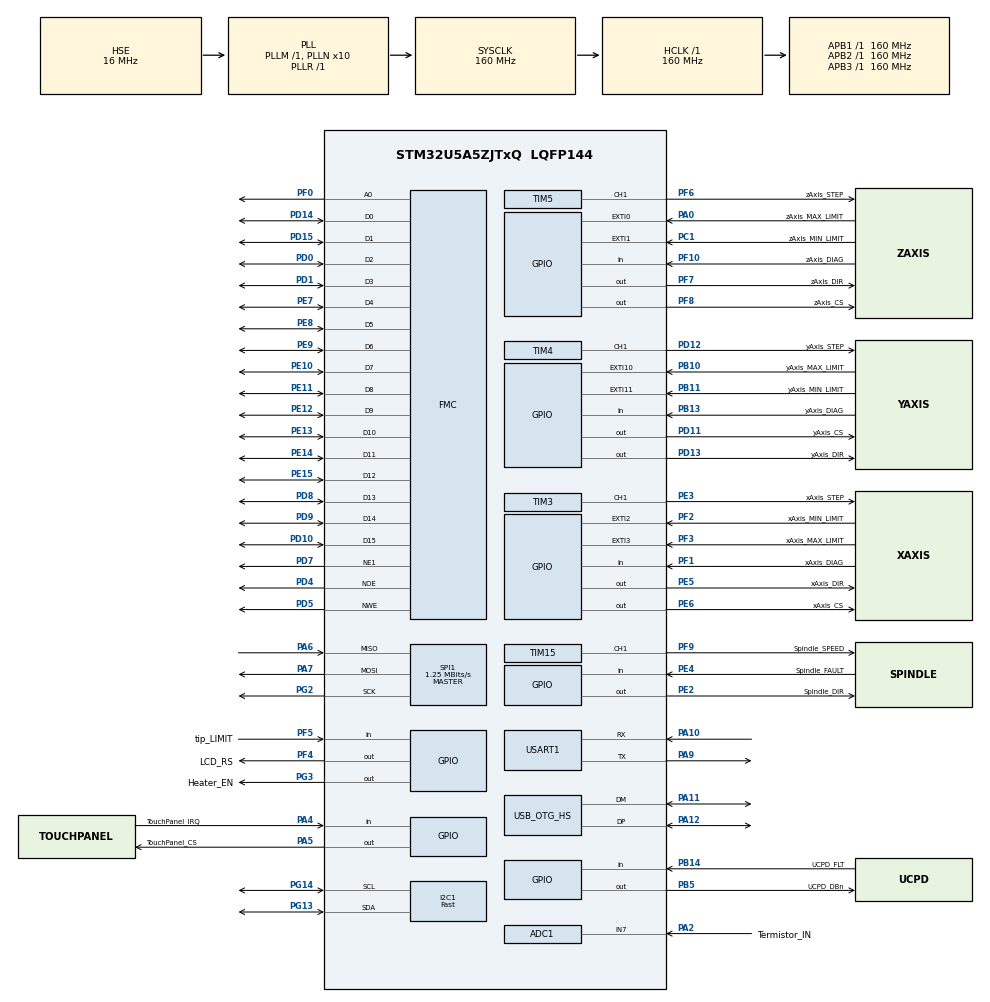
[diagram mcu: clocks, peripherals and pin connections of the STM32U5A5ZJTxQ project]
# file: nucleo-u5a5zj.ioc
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ADC1.Channel-5\#ChannelRegularConversion=ADC_CHANNEL_7
ADC1.MonitoredBy-5\#ChannelRegularConversion=__NULL
ADC1.NbrOfConversionFlag=1
ADC1.OffsetNumber-5\#ChannelRegularConversion=ADC_OFFSET_NONE
ADC1.Rank-5\#ChannelRegularConversion=1
ADC1.SamplingTime-5\#ChannelRegularConversion=ADC_SAMPLETIME_5CYCLE
ADC1.master=1
CORTEX_M33_NS.userName=CORTEX_M33
FMC.AddressSetupTime1=3
FMC.BusTurnAroundDuration1=2
FMC.DataHoldTime1=2
FMC.DataSetupTime1=2
I2C1.I2C_Speed_Mode=I2C_Fast
I2C1.Timing=0x00F07BFF
Mcu.Family=STM32U5
Mcu.Name=STM32U5A5ZJTxQ
Mcu.Package=LQFP144
NUCLEO-U5A5ZJ-Q.BUTTON=2
NUCLEO-U5A5ZJ-Q.LD1=true
NUCLEO-U5A5ZJ-Q.LD2=true
NUCLEO-U5A5ZJ-Q.LD3=false
NVIC.EXTI0_IRQn=true\:0\:0\:false\:false\:true\:true\:true\:true
NVIC.EXTI10_IRQn=true\:0\:0\:false\:false\:true\:true\:true\:true
NVIC.EXTI11_IRQn=true\:0\:0\:false\:false\:true\:true\:true\:true
NVIC.EXTI1_IRQn=true\:0\:0\:false\:false\:true\:true\:true\:true
NVIC.EXTI2_IRQn=true\:0\:0\:false\:false\:true\:true\:true\:true
NVIC.EXTI3_IRQn=true\:0\:0\:false\:false\:true\:true\:true\:true
NVIC.PriorityGroup=NVIC_PRIORITYGROUP_4
NVIC.TIM3_IRQn=true\:0\:0\:false\:false\:true\:true\:true\:true
NVIC.TIM4_IRQn=true\:0\:0\:false\:false\:true\:true\:true\:true
NVIC.TIM5_IRQn=true\:0\:0\:false\:false\:true\:true\:true\:true
PA0.GPIO_Label=zAxis_MAX_LIMIT
PA0.GPIO_ModeDefaultEXTI=GPIO_MODE_IT_RISING_FALLING
PA0.GPIO_PuPd=GPIO_PULLUP
PA0.Signal=GPXTI0
PA10.Mode=Asynchronous
PA10.Signal=USART1_RX
PA11.Mode=Internal_Phy_Device
PA11.Signal=USB_OTG_HS_DM
PA12.Mode=Internal_Phy_Device
PA12.Signal=USB_OTG_HS_DP
PA13\ (JTMS/SWDIO).Mode=Trace_Asynchronous_SW
PA13\ (JTMS/SWDIO).Signal=DEBUG_JTMS-SWDIO
PA14\ (JTCK/SWCLK).Mode=Trace_Asynchronous_SW
PA14\ (JTCK/SWCLK).Signal=DEBUG_JTCK-SWCLK
PA15\ (JTDI).Signal=UCPD1_CC1
PA2.GPIO_Label=Termistor_IN
PA2.Mode=IN7-Single-Ended
PA2.Signal=ADC1_IN7
PA4.GPIO_Label=TouchPanel_IRQ
PA4.Signal=GPIO_Input
PA5.GPIO_Label=TouchPanel_CS
PA5.Signal=GPIO_Output
PA6.Mode=Full_Duplex_Master
PA6.Signal=SPI1_MISO
PA7.Mode=Full_Duplex_Master
PA7.Signal=SPI1_MOSI
PA9.Mode=Asynchronous
PA9.Signal=USART1_TX
PB10.GPIO_Label=yAxis_MAX_LIMIT
PB10.GPIO_ModeDefaultEXTI=GPIO_MODE_IT_FALLING
PB10.GPIO_PuPd=GPIO_PULLUP
PB10.Signal=GPXTI10
PB11.GPIO_Label=yAxis_MIN_LIMIT
PB11.GPIO_ModeDefaultEXTI=GPIO_MODE_IT_FALLING
PB11.GPIO_PuPd=GPIO_PULLUP
PB11.Signal=GPXTI11
PB13.GPIO_Label=yAxis_DIAG
PB13.Signal=GPIO_Input
PB14.GPIO_Label=UCPD_FLT
PB14.Signal=GPIO_Input
PB15.Signal=UCPD1_CC2
PB3\ (JTDO/TRACESWO).Mode=Trace_Asynchronous_SW
PB3\ (JTDO/TRACESWO).Signal=DEBUG_JTDO-SWO
PB5.GPIO_Label=UCPD_DBn
PB5.Signal=GPIO_Output
PC1.GPIO_Label=zAxis_MIN_LIMIT
PC1.GPIO_ModeDefaultEXTI=GPIO_MODE_IT_FALLING
PC1.GPIO_PuPd=GPIO_PULLUP
PC1.Signal=GPXTI1
PC14-OSC32_IN\ (PC14).Mode=LSE-External-Oscillator
PC14-OSC32_IN\ (PC14).Signal=RCC_OSC32_IN
PC15-OSC32_OUT\ (PC15).Mode=LSE-External-Oscillator
PC15-OSC32_OUT\ (PC15).Signal=RCC_OSC32_OUT
PD0.Signal=FMC_D2_DA2
PD1.Signal=FMC_D3_DA3
PD10.Signal=FMC_D15_DA15
PD11.GPIO_Label=yAxis_CS
PD11.Signal=GPIO_Output
PD12.GPIO_Label=yAxis_STEP
PD12.Signal=S_TIM4_CH1
PD13.GPIO_Label=yAxis_DIR
PD13.Signal=GPIO_Output
PD14.Signal=FMC_D0_DA0
PD15.Signal=FMC_D1_DA1
PD4.Signal=FMC_NOE
PD5.Signal=FMC_NWE
PD7.Mode=NorPsramChipSelect1_1
PD7.Signal=FMC_NE1
PD8.Signal=FMC_D13_DA13
PD9.Signal=FMC_D14_DA14
PE10.Signal=FMC_D7_DA7
PE11.Signal=FMC_D8_DA8
PE12.Signal=FMC_D9_DA9
PE13.Signal=FMC_D10_DA10
PE14.Signal=FMC_D11_DA11
PE15.Signal=FMC_D12_DA12
PE2.GPIO_Label=Spindle_DIR
PE2.Signal=GPIO_Output
PE3.GPIO_Label=xAxis_STEP
PE3.Signal=S_TIM3_CH1
PE4.GPIO_Label=Spindle_FAULT
PE4.Signal=GPIO_Input
PE5.GPIO_Label=xAxis_DIR
PE5.Signal=GPIO_Output
PE6.GPIO_Label=xAxis_CS
PE6.Signal=GPIO_Output
PE7.Signal=FMC_D4_DA4
PE8.Signal=FMC_D5_DA5
PE9.Signal=FMC_D6_DA6
PF0.Signal=FMC_A0
PF1.GPIO_Label=xAxis_DIAG
PF1.Signal=GPIO_Input
PF10.GPIO_Label=zAxis_DIAG
PF10.Signal=GPIO_Input
PF2.GPIO_Label=xAxis_MIN_LIMIT
PF2.GPIO_ModeDefaultEXTI=GPIO_MODE_IT_FALLING
PF2.GPIO_PuPd=GPIO_PULLUP
PF2.Signal=GPXTI2
PF3.GPIO_Label=xAxis_MAX_LIMIT
PF3.GPIO_ModeDefaultEXTI=GPIO_MODE_IT_FALLING
PF3.GPIO_PuPd=GPIO_PULLUP
PF3.Signal=GPXTI3
PF4.GPIO_Label=LCD_RS
PF4.Signal=GPIO_Output
PF5.GPIO_Label=tip_LIMIT
PF5.GPIO_PuPd=GPIO_PULLUP
PF5.Signal=GPIO_Input
PF6.GPIO_Label=zAxis_STEP
PF6.Signal=S_TIM5_CH1
PF7.GPIO_Label=zAxis_DIR
PF7.Signal=GPIO_Output
PF8.GPIO_Label=zAxis_CS
PF8.Signal=GPIO_Output
PF9.GPIO_Label=Spindle_SPEED
PF9.Signal=S_TIM15_CH1
PG13.Mode=I2C
PG13.Signal=I2C1_SDA
PG14.Mode=I2C
PG14.Signal=I2C1_SCL
PG2.Mode=Full_Duplex_Master
PG2.Signal=SPI1_SCK
PG3.GPIO_Label=Heater_EN
PG3.Signal=GPIO_Output
PH0-OSC_IN\ (PH0).Mode=HSE-External-Oscillator
PH0-OSC_IN\ (PH0).Signal=RCC_OSC_IN
PH1-OSC_OUT\ (PH1).Mode=HSE-External-Oscillator
PH1-OSC_OUT\ (PH1).Signal=RCC_OSC_OUT
PWR.PowerMode=PWR_SMPS_SUPPLY
ProjectManager.HeapSize=0x200
ProjectManager.StackSize=0x400
ProjectManager.TargetToolchain=STM32CubeIDE
RCC.ADCCLockSelection=RCC_ADCDACCLKSOURCE_HSE
RCC.ADCFreq_Value=16000000
RCC.AHBFreq_Value=160000000
RCC.APB1Freq_Value=160000000
RCC.APB1TimFreq_Value=160000000
RCC.APB2Freq_Value=160000000
RCC.APB2TimFreq_Value=160000000
RCC.APB3Freq_Value=160000000
RCC.CortexFreq_Value=160000000
RCC.DACCLockSelectionVirtual=RCC_DAC1CLKSOURCE_LSI
RCC.EPOD_VALUE=16000000
RCC.HCLKFreq_Value=160000000
RCC.HSE_VALUE=16000000
RCC.HSI48_VALUE=48000000
RCC.HSI_VALUE=16000000
RCC.LSIDIV_VALUE=32000
RCC.MSIClockRange=RCC_MSIRANGE_0
RCC.MSI_VALUE=48000000
RCC.PLL1P=8
RCC.PLL1R=1
RCC.PLL2FRACN=0
RCC.PLL3FRACN=0
RCC.PLLFRACN=0
RCC.PLLN=10
RCC.PLLSourceVirtual=RCC_PLLSOURCE_HSE
RCC.SYSCLKFreq_VALUE=160000000
RCC.SYSCLKSource=RCC_SYSCLKSOURCE_PLLCLK
RCC.USBPHYCLockSelection=RCC_USBPHYCLKSOURCE_HSE
RCC.VCOOutputFreq_Value=160000000
SH.FMC_A0.0=FMC_A0,A0_1
SH.FMC_D0_DA0.0=FMC_D0,16b-d1
SH.FMC_D10_DA10.0=FMC_D10,16b-d1
SH.FMC_D11_DA11.0=FMC_D11,16b-d1
SH.FMC_D12_DA12.0=FMC_D12,16b-d1
SH.FMC_D13_DA13.0=FMC_D13,16b-d1
SH.FMC_D14_DA14.0=FMC_D14,16b-d1
SH.FMC_D15_DA15.0=FMC_D15,16b-d1
SH.FMC_D1_DA1.0=FMC_D1,16b-d1
SH.FMC_D2_DA2.0=FMC_D2,16b-d1
SH.FMC_D3_DA3.0=FMC_D3,16b-d1
SH.FMC_D4_DA4.0=FMC_D4,16b-d1
SH.FMC_D5_DA5.0=FMC_D5,16b-d1
SH.FMC_D6_DA6.0=FMC_D6,16b-d1
SH.FMC_D7_DA7.0=FMC_D7,16b-d1
SH.FMC_D8_DA8.0=FMC_D8,16b-d1
SH.FMC_D9_DA9.0=FMC_D9,16b-d1
SH.FMC_NOE.0=FMC_NOE,Lcd1
SH.FMC_NWE.0=FMC_NWE,Lcd1
SH.S_TIM15_CH1.0=TIM15_CH1,PWM Generation1 CH1
SH.S_TIM3_CH1.0=TIM3_CH1,Output Compare1 CH1
SH.S_TIM4_CH1.0=TIM4_CH1,Output Compare1 CH1
SH.S_TIM5_CH1.0=TIM5_CH1,Output Compare1 CH1
SPI1.BaudRatePrescaler=SPI_BAUDRATEPRESCALER_128
SPI1.CalculateBaudRate=1.25 MBits/s
SPI1.DataSize=SPI_DATASIZE_8BIT
SPI1.Direction=SPI_DIRECTION_2LINES
SPI1.Mode=SPI_MODE_MASTER
SPI1.VirtualType=VM_MASTER
STMicroelectronics.X-CUBE-TOUCHGFX.4.26.0.ApplicationCcGraphicsJjApplication=TouchGFXOoGenerator
STMicroelectronics.X-CUBE-TOUCHGFX.4.26.0.tgfx_buffering_strategy=Double
STMicroelectronics.X-CUBE-TOUCHGFX.4.26.0.tgfx_custom_height=800
STMicroelectronics.X-CUBE-TOUCHGFX.4.26.0.tgfx_custom_width=480
STMicroelectronics.X-CUBE-TOUCHGFX.4.26.0.tgfx_display_interface=disp_fmc
STMicroelectronics.X-CUBE-TOUCHGFX.4.26.0.tgfx_hardware_accelerator=dma_2d
STMicroelectronics.X-CUBE-TOUCHGFX.4.26.0.tgfx_location=Allocate
STMicroelectronics.X-CUBE-TOUCHGFX.4.26.0_IsPackSelfContextualization=true
TIM15.Channel-PWM\ Generation1\ CH1=TIM_CHANNEL_1
TIM15.Prescaler=159
TIM3.Channel-Output\ Compare1\ CH1=TIM_CHANNEL_1
TIM3.OCMode_1=TIM_OCMODE_TOGGLE
TIM3.Prescaler=159
TIM3.PulseNoDither_1=4294967295
TIM4.Channel-Output\ Compare1\ CH1=TIM_CHANNEL_1
TIM4.OCMode_1=TIM_OCMODE_TOGGLE
TIM4.Prescaler=159
TIM4.PulseNoDither_1=4294967295
TIM5.Channel-Output\ Compare1\ CH1=TIM_CHANNEL_1
TIM5.OCMode_1=TIM_OCMODE_TOGGLE
TIM5.Prescaler=159
TIM5.PulseNoDither_1=4294967295
USART1.VirtualMode-Asynchronous=VM_ASYNC
USB_OTG_HS.VirtualMode=Device_HS
VP_CRC_VS_CRC.Mode=CRC_Activate
VP_DMA2D_VS_DMA2D.Mode=DMA2D_Activate
VP_ICACHE_VS_ICACHE.Mode=DirectMappedCache
VP_LPBAMQUEUE_VS_QUEUE.Mode=QUEUEMODE
VP_LPBAM_VS_SIG1.Mode=SmartRun
VP_LPBAM_VS_SIG4.Mode=LPDMA1
VP_MEMORYMAP_VS_MEMORYMAP.Mode=CurAppReg
VP_NUCLEO-U5A5ZJ-Q_VS_BSP_COMMON.Mode=COMMON
VP_PWR_VS_DBSignals.Mode=DisableDeadBatterySignals
VP_PWR_VS_LPOM.Mode=PowerOptimisation
VP_PWR_VS_SECSignals.Mode=Security/Privilege
VP_PWR_Vdda.Mode=isolationVdda
VP_STMicroelectronics.X-CUBE-TOUCHGFX_VS_GraphicsJjApplication_4.26.0.Mode=GraphicsJjApplication
VP_TIM15_VS_ClockSourceINT.Mode=Internal
VP_TIM3_VS_ClockSourceINT.Mode=Internal
VP_TIM4_VS_ClockSourceINT.Mode=Internal
VP_TIM5_VS_ClockSourceINT.Mode=Internal
board=NUCLEO-U5A5ZJ-Q

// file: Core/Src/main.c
/* USER CODE BEGIN Header */
/**
 ******************************************************************************
 * @file           : main.c
 * @brief          : Main program body
 ******************************************************************************
 * @attention
 *3
 * Copyright (c) 2025 STMicroelectronics.
 * All rights reserved.
 *
 * This software is licensed under terms that can be found in the LICENSE
 * file in the root directory of this software component. If no LICENSE
 * file comes with this software, it is provided AS-IS.
 *
 ******************************************************************************
 */
/* USER CODE END Header */
#include "main.h"
#include "app_touchgfx.h"

ADC_HandleTypeDef hadc1;

CRC_HandleTypeDef hcrc;

DMA2D_HandleTypeDef hdma2d;

I2C_HandleTypeDef hi2c1;

SPI_HandleTypeDef hspi1;

TIM_HandleTypeDef htim3;
TIM_HandleTypeDef htim4;
TIM_HandleTypeDef htim5;
TIM_HandleTypeDef htim15;

UART_HandleTypeDef huart1;

PCD_HandleTypeDef hpcd_USB_OTG_HS;

SRAM_HandleTypeDef hsram1;

void SystemClock_Config(void);
static void SystemPower_Config(void);
static void MX_GPIO_Init(void);
static void MX_ICACHE_Init(void);
static void MX_USB_OTG_HS_PCD_Init(void);
static void MX_ADC1_Init(void);
static void MX_CRC_Init(void);
static void MX_DMA2D_Init(void);
static void MX_FMC_Init(void);
static void MX_SPI1_Init(void);
static void MX_USART1_UART_Init(void);
static void MX_TIM3_Init(void);
static void MX_TIM4_Init(void);
static void MX_TIM5_Init(void);
static void MX_TIM15_Init(void);
static void MX_I2C1_Init(void);

int main(void)
{

  /* MCU Configuration--------------------------------------------------------*/

  /* Reset of all peripherals, Initializes the Flash interface and the Systick. */
  HAL_Init();

  /* Configure the System Power */
  SystemPower_Config();

  /* Configure the system clock */
  SystemClock_Config();

  /* Initialize all configured peripherals */
  MX_GPIO_Init();
  MX_ICACHE_Init();
  MX_USB_OTG_HS_PCD_Init();
  MX_ADC1_Init();
  MX_CRC_Init();
  MX_DMA2D_Init();
  MX_FMC_Init();
  MX_SPI1_Init();
  MX_USART1_UART_Init();
  MX_TIM3_Init();
  MX_TIM4_Init();
  MX_TIM5_Init();
  MX_TIM15_Init();
  MX_I2C1_Init();
  MX_TouchGFX_Init();

  /* Initialize leds */
  BSP_LED_Init(LED_GREEN);
  BSP_LED_Init(LED_BLUE);

  /* Initialize User push-button without interrupt mode. */
  BSP_PB_Init(BUTTON_USER, BUTTON_MODE_GPIO);

  /* Infinite loop */
  /* USER CODE BEGIN WHILE */
    ATC_Init();

    while (1) {
        ATC_Loop();

    /* USER CODE END WHILE */

  MX_TouchGFX_Process();
    }
}

void SystemClock_Config(void)
{
  RCC_OscInitTypeDef RCC_OscInitStruct = {0};
  RCC_ClkInitTypeDef RCC_ClkInitStruct = {0};

  /** Configure the main internal regulator output voltage
  */
  if (HAL_PWREx_ControlVoltageScaling(PWR_REGULATOR_VOLTAGE_SCALE1) != HAL_OK)
  {
    Error_Handler();
  }

  /** Initializes the CPU, AHB and APB buses clocks
  */
  RCC_OscInitStruct.OscillatorType = RCC_OSCILLATORTYPE_HSE;
  RCC_OscInitStruct.HSEState = RCC_HSE_ON;
  RCC_OscInitStruct.PLL.PLLState = RCC_PLL_ON;
  RCC_OscInitStruct.PLL.PLLSource = RCC_PLLSOURCE_HSE;
  RCC_OscInitStruct.PLL.PLLMBOOST = RCC_PLLMBOOST_DIV1;
  RCC_OscInitStruct.PLL.PLLM = 1;
  RCC_OscInitStruct.PLL.PLLN = 10;
  RCC_OscInitStruct.PLL.PLLP = 8;
  RCC_OscInitStruct.PLL.PLLQ = 2;
  RCC_OscInitStruct.PLL.PLLR = 1;
  RCC_OscInitStruct.PLL.PLLRGE = RCC_PLLVCIRANGE_1;
  RCC_OscInitStruct.PLL.PLLFRACN = 0;
  if (HAL_RCC_OscConfig(&RCC_OscInitStruct) != HAL_OK)
  {
    Error_Handler();
  }

  /** Initializes the CPU, AHB and APB buses clocks
  */
  RCC_ClkInitStruct.ClockType = RCC_CLOCKTYPE_HCLK|RCC_CLOCKTYPE_SYSCLK
                              |RCC_CLOCKTYPE_PCLK1|RCC_CLOCKTYPE_PCLK2
                              |RCC_CLOCKTYPE_PCLK3;
  RCC_ClkInitStruct.SYSCLKSource = RCC_SYSCLKSOURCE_PLLCLK;
  RCC_ClkInitStruct.AHBCLKDivider = RCC_SYSCLK_DIV1;
  RCC_ClkInitStruct.APB1CLKDivider = RCC_HCLK_DIV1;
  RCC_ClkInitStruct.APB2CLKDivider = RCC_HCLK_DIV1;
  RCC_ClkInitStruct.APB3CLKDivider = RCC_HCLK_DIV1;

  if (HAL_RCC_ClockConfig(&RCC_ClkInitStruct, FLASH_LATENCY_4) != HAL_OK)
  {
    Error_Handler();
  }
}

/**
  * @brief Power Configuration
  * @retval None
  */
static void SystemPower_Config(void)
{
  HAL_PWREx_EnableVddIO2();

  /*
   * Disable the internal Pull-Up in Dead Battery pins of UCPD peripheral
   */
  HAL_PWREx_DisableUCPDDeadBattery();

  /*
   * Switch to SMPS regulator instead of LDO
   */
  if (HAL_PWREx_ConfigSupply(PWR_SMPS_SUPPLY) != HAL_OK)
  {
    Error_Handler();
  }
}

static void MX_ADC1_Init(void)
{

  ADC_ChannelConfTypeDef sConfig = {0};

  /** Common config
  */
  hadc1.Instance = ADC1;
  hadc1.Init.ClockPrescaler = ADC_CLOCK_ASYNC_DIV1;
  hadc1.Init.Resolution = ADC_RESOLUTION_14B;
  hadc1.Init.GainCompensation = 0;
  hadc1.Init.DataAlign = ADC_DATAALIGN_RIGHT;
  hadc1.Init.ScanConvMode = ADC_SCAN_DISABLE;
  hadc1.Init.EOCSelection = ADC_EOC_SINGLE_CONV;
  hadc1.Init.LowPowerAutoWait = DISABLE;
  hadc1.Init.ContinuousConvMode = DISABLE;
  hadc1.Init.NbrOfConversion = 1;
  hadc1.Init.DiscontinuousConvMode = DISABLE;
  hadc1.Init.ExternalTrigConv = ADC_SOFTWARE_START;
  hadc1.Init.ExternalTrigConvEdge = ADC_EXTERNALTRIGCONVEDGE_NONE;
  hadc1.Init.DMAContinuousRequests = DISABLE;
  hadc1.Init.TriggerFrequencyMode = ADC_TRIGGER_FREQ_HIGH;
  hadc1.Init.Overrun = ADC_OVR_DATA_PRESERVED;
  hadc1.Init.LeftBitShift = ADC_LEFTBITSHIFT_NONE;
  hadc1.Init.ConversionDataManagement = ADC_CONVERSIONDATA_DR;
  hadc1.Init.OversamplingMode = DISABLE;
  if (HAL_ADC_Init(&hadc1) != HAL_OK)
  {
    Error_Handler();
  }

  /** Configure Regular Channel
  */
  sConfig.Channel = ADC_CHANNEL_7;
  sConfig.Rank = ADC_REGULAR_RANK_1;
  sConfig.SamplingTime = ADC_SAMPLETIME_5CYCLE;
  sConfig.SingleDiff = ADC_SINGLE_ENDED;
  sConfig.OffsetNumber = ADC_OFFSET_NONE;
  sConfig.Offset = 0;
  if (HAL_ADC_ConfigChannel(&hadc1, &sConfig) != HAL_OK)
  {
    Error_Handler();
  }

}

static void MX_CRC_Init(void)
{

  hcrc.Instance = CRC;
  hcrc.Init.DefaultPolynomialUse = DEFAULT_POLYNOMIAL_ENABLE;
  hcrc.Init.DefaultInitValueUse = DEFAULT_INIT_VALUE_ENABLE;
  hcrc.Init.InputDataInversionMode = CRC_INPUTDATA_INVERSION_NONE;
  hcrc.Init.OutputDataInversionMode = CRC_OUTPUTDATA_INVERSION_DISABLE;
  hcrc.InputDataFormat = CRC_INPUTDATA_FORMAT_BYTES;
  if (HAL_CRC_Init(&hcrc) != HAL_OK)
  {
    Error_Handler();
  }

}

static void MX_DMA2D_Init(void)
{

  hdma2d.Instance = DMA2D;
  hdma2d.Init.Mode = DMA2D_M2M;
  hdma2d.Init.ColorMode = DMA2D_OUTPUT_ARGB8888;
  hdma2d.Init.OutputOffset = 0;
  hdma2d.Init.BytesSwap = DMA2D_BYTES_REGULAR;
  hdma2d.Init.LineOffsetMode = DMA2D_LOM_PIXELS;
  hdma2d.LayerCfg[1].InputOffset = 0;
  hdma2d.LayerCfg[1].InputColorMode = DMA2D_INPUT_ARGB8888;
  hdma2d.LayerCfg[1].AlphaMode = DMA2D_NO_MODIF_ALPHA;
  hdma2d.LayerCfg[1].InputAlpha = 0;
  hdma2d.LayerCfg[1].AlphaInverted = DMA2D_REGULAR_ALPHA;
  hdma2d.LayerCfg[1].RedBlueSwap = DMA2D_RB_REGULAR;
  if (HAL_DMA2D_Init(&hdma2d) != HAL_OK)
  {
    Error_Handler();
  }
  if (HAL_DMA2D_ConfigLayer(&hdma2d, 1) != HAL_OK)
  {
    Error_Handler();
  }

}

static void MX_I2C1_Init(void)
{

  hi2c1.Instance = I2C1;
  hi2c1.Init.Timing = 0x00F07BFF;
  hi2c1.Init.OwnAddress1 = 0;
  hi2c1.Init.AddressingMode = I2C_ADDRESSINGMODE_7BIT;
  hi2c1.Init.DualAddressMode = I2C_DUALADDRESS_DISABLE;
  hi2c1.Init.OwnAddress2 = 0;
  hi2c1.Init.OwnAddress2Masks = I2C_OA2_NOMASK;
  hi2c1.Init.GeneralCallMode = I2C_GENERALCALL_DISABLE;
  hi2c1.Init.NoStretchMode = I2C_NOSTRETCH_DISABLE;
  if (HAL_I2C_Init(&hi2c1) != HAL_OK)
  {
    Error_Handler();
  }

  /** Configure Analogue filter
  */
  if (HAL_I2CEx_ConfigAnalogFilter(&hi2c1, I2C_ANALOGFILTER_ENABLE) != HAL_OK)
  {
    Error_Handler();
  }

  /** Configure Digital filter
  */
  if (HAL_I2CEx_ConfigDigitalFilter(&hi2c1, 0) != HAL_OK)
  {
    Error_Handler();
  }

}

static void MX_ICACHE_Init(void)
{

  /** Enable instruction cache in 1-way (direct mapped cache)
  */
  if (HAL_ICACHE_ConfigAssociativityMode(ICACHE_1WAY) != HAL_OK)
  {
    Error_Handler();
  }
  if (HAL_ICACHE_Enable() != HAL_OK)
  {
    Error_Handler();
  }

}

static void MX_SPI1_Init(void)
{

  SPI_AutonomousModeConfTypeDef HAL_SPI_AutonomousMode_Cfg_Struct = {0};

  /* SPI1 parameter configuration*/
  hspi1.Instance = SPI1;
  hspi1.Init.Mode = SPI_MODE_MASTER;
  hspi1.Init.Direction = SPI_DIRECTION_2LINES;
  hspi1.Init.DataSize = SPI_DATASIZE_8BIT;
  hspi1.Init.CLKPolarity = SPI_POLARITY_LOW;
  hspi1.Init.CLKPhase = SPI_PHASE_1EDGE;
  hspi1.Init.NSS = SPI_NSS_SOFT;
  hspi1.Init.BaudRatePrescaler = SPI_BAUDRATEPRESCALER_128;
  hspi1.Init.FirstBit = SPI_FIRSTBIT_MSB;
  hspi1.Init.TIMode = SPI_TIMODE_DISABLE;
  hspi1.Init.CRCCalculation = SPI_CRCCALCULATION_DISABLE;
  hspi1.Init.CRCPolynomial = 0x7;
  hspi1.Init.NSSPMode = SPI_NSS_PULSE_ENABLE;
  hspi1.Init.NSSPolarity = SPI_NSS_POLARITY_LOW;
  hspi1.Init.FifoThreshold = SPI_FIFO_THRESHOLD_01DATA;
  hspi1.Init.MasterSSIdleness = SPI_MASTER_SS_IDLENESS_00CYCLE;
  hspi1.Init.MasterInterDataIdleness = SPI_MASTER_INTERDATA_IDLENESS_00CYCLE;
  hspi1.Init.MasterReceiverAutoSusp = SPI_MASTER_RX_AUTOSUSP_DISABLE;
  hspi1.Init.MasterKeepIOState = SPI_MASTER_KEEP_IO_STATE_DISABLE;
  hspi1.Init.IOSwap = SPI_IO_SWAP_DISABLE;
  hspi1.Init.ReadyMasterManagement = SPI_RDY_MASTER_MANAGEMENT_INTERNALLY;
  hspi1.Init.ReadyPolarity = SPI_RDY_POLARITY_HIGH;
  if (HAL_SPI_Init(&hspi1) != HAL_OK)
  {
    Error_Handler();
  }
  HAL_SPI_AutonomousMode_Cfg_Struct.TriggerState = SPI_AUTO_MODE_DISABLE;
  HAL_SPI_AutonomousMode_Cfg_Struct.TriggerSelection = SPI_GRP1_GPDMA_CH0_TCF_TRG;
  HAL_SPI_AutonomousMode_Cfg_Struct.TriggerPolarity = SPI_TRIG_POLARITY_RISING;
  if (HAL_SPIEx_SetConfigAutonomousMode(&hspi1, &HAL_SPI_AutonomousMode_Cfg_Struct) != HAL_OK)
  {
    Error_Handler();
  }

}

static void MX_TIM3_Init(void)
{

  TIM_ClockConfigTypeDef sClockSourceConfig = {0};
  TIM_MasterConfigTypeDef sMasterConfig = {0};
  TIM_OC_InitTypeDef sConfigOC = {0};

  htim3.Instance = TIM3;
  htim3.Init.Prescaler = 159;
  htim3.Init.CounterMode = TIM_COUNTERMODE_UP;
  htim3.Init.Period = 4294967295;
  htim3.Init.ClockDivision = TIM_CLOCKDIVISION_DIV1;
  htim3.Init.AutoReloadPreload = TIM_AUTORELOAD_PRELOAD_DISABLE;
  if (HAL_TIM_Base_Init(&htim3) != HAL_OK)
  {
    Error_Handler();
  }
  sClockSourceConfig.ClockSource = TIM_CLOCKSOURCE_INTERNAL;
  if (HAL_TIM_ConfigClockSource(&htim3, &sClockSourceConfig) != HAL_OK)
  {
    Error_Handler();
  }
  if (HAL_TIM_OC_Init(&htim3) != HAL_OK)
  {
    Error_Handler();
  }
  sMasterConfig.MasterOutputTrigger = TIM_TRGO_RESET;
  sMasterConfig.MasterSlaveMode = TIM_MASTERSLAVEMODE_DISABLE;
  if (HAL_TIMEx_MasterConfigSynchronization(&htim3, &sMasterConfig) != HAL_OK)
  {
    Error_Handler();
  }
  sConfigOC.OCMode = TIM_OCMODE_TOGGLE;
  sConfigOC.Pulse = 4294967295;
  sConfigOC.OCPolarity = TIM_OCPOLARITY_HIGH;
  sConfigOC.OCFastMode = TIM_OCFAST_DISABLE;
  if (HAL_TIM_OC_ConfigChannel(&htim3, &sConfigOC, TIM_CHANNEL_1) != HAL_OK)
  {
    Error_Handler();
  }
  HAL_TIM_MspPostInit(&htim3);

}

static void MX_TIM4_Init(void)
{

  TIM_ClockConfigTypeDef sClockSourceConfig = {0};
  TIM_MasterConfigTypeDef sMasterConfig = {0};
  TIM_OC_InitTypeDef sConfigOC = {0};

  htim4.Instance = TIM4;
  htim4.Init.Prescaler = 159;
  htim4.Init.CounterMode = TIM_COUNTERMODE_UP;
  htim4.Init.Period = 4294967295;
  htim4.Init.ClockDivision = TIM_CLOCKDIVISION_DIV1;
  htim4.Init.AutoReloadPreload = TIM_AUTORELOAD_PRELOAD_DISABLE;
  if (HAL_TIM_Base_Init(&htim4) != HAL_OK)
  {
    Error_Handler();
  }
  sClockSourceConfig.ClockSource = TIM_CLOCKSOURCE_INTERNAL;
  if (HAL_TIM_ConfigClockSource(&htim4, &sClockSourceConfig) != HAL_OK)
  {
    Error_Handler();
  }
  if (HAL_TIM_OC_Init(&htim4) != HAL_OK)
  {
    Error_Handler();
  }
  sMasterConfig.MasterOutputTrigger = TIM_TRGO_RESET;
  sMasterConfig.MasterSlaveMode = TIM_MASTERSLAVEMODE_DISABLE;
  if (HAL_TIMEx_MasterConfigSynchronization(&htim4, &sMasterConfig) != HAL_OK)
  {
    Error_Handler();
  }
  sConfigOC.OCMode = TIM_OCMODE_TOGGLE;
  sConfigOC.Pulse = 4294967295;
  sConfigOC.OCPolarity = TIM_OCPOLARITY_HIGH;
  sConfigOC.OCFastMode = TIM_OCFAST_DISABLE;
  if (HAL_TIM_OC_ConfigChannel(&htim4, &sConfigOC, TIM_CHANNEL_1) != HAL_OK)
  {
    Error_Handler();
  }
  HAL_TIM_MspPostInit(&htim4);

}

static void MX_TIM5_Init(void)
{

  TIM_ClockConfigTypeDef sClockSourceConfig = {0};
  TIM_MasterConfigTypeDef sMasterConfig = {0};
  TIM_OC_InitTypeDef sConfigOC = {0};

  htim5.Instance = TIM5;
  htim5.Init.Prescaler = 159;
  htim5.Init.CounterMode = TIM_COUNTERMODE_UP;
  htim5.Init.Period = 4294967295;
  htim5.Init.ClockDivision = TIM_CLOCKDIVISION_DIV1;
  htim5.Init.AutoReloadPreload = TIM_AUTORELOAD_PRELOAD_DISABLE;
  if (HAL_TIM_Base_Init(&htim5) != HAL_OK)
  {
    Error_Handler();
  }
  sClockSourceConfig.ClockSource = TIM_CLOCKSOURCE_INTERNAL;
  if (HAL_TIM_ConfigClockSource(&htim5, &sClockSourceConfig) != HAL_OK)
  {
    Error_Handler();
  }
  if (HAL_TIM_OC_Init(&htim5) != HAL_OK)
  {
    Error_Handler();
  }
  sMasterConfig.MasterOutputTrigger = TIM_TRGO_RESET;
  sMasterConfig.MasterSlaveMode = TIM_MASTERSLAVEMODE_DISABLE;
  if (HAL_TIMEx_MasterConfigSynchronization(&htim5, &sMasterConfig) != HAL_OK)
  {
    Error_Handler();
  }
  sConfigOC.OCMode = TIM_OCMODE_TOGGLE;
  sConfigOC.Pulse = 4294967295;
  sConfigOC.OCPolarity = TIM_OCPOLARITY_HIGH;
  sConfigOC.OCFastMode = TIM_OCFAST_DISABLE;
  if (HAL_TIM_OC_ConfigChannel(&htim5, &sConfigOC, TIM_CHANNEL_1) != HAL_OK)
  {
    Error_Handler();
  }
  HAL_TIM_MspPostInit(&htim5);

}

static void MX_TIM15_Init(void)
{

  TIM_ClockConfigTypeDef sClockSourceConfig = {0};
  TIM_MasterConfigTypeDef sMasterConfig = {0};
  TIM_OC_InitTypeDef sConfigOC = {0};
  TIM_BreakDeadTimeConfigTypeDef sBreakDeadTimeConfig = {0};

  htim15.Instance = TIM15;
  htim15.Init.Prescaler = 159;
  htim15.Init.CounterMode = TIM_COUNTERMODE_UP;
  htim15.Init.Period = 65535;
  htim15.Init.ClockDivision = TIM_CLOCKDIVISION_DIV1;
  htim15.Init.RepetitionCounter = 0;
  htim15.Init.AutoReloadPreload = TIM_AUTORELOAD_PRELOAD_DISABLE;
  if (HAL_TIM_Base_Init(&htim15) != HAL_OK)
  {
    Error_Handler();
  }
  sClockSourceConfig.ClockSource = TIM_CLOCKSOURCE_INTERNAL;
  if (HAL_TIM_ConfigClockSource(&htim15, &sClockSourceConfig) != HAL_OK)
  {
    Error_Handler();
  }
  if (HAL_TIM_PWM_Init(&htim15) != HAL_OK)
  {
    Error_Handler();
  }
  sMasterConfig.MasterOutputTrigger = TIM_TRGO_RESET;
  sMasterConfig.MasterSlaveMode = TIM_MASTERSLAVEMODE_DISABLE;
  if (HAL_TIMEx_MasterConfigSynchronization(&htim15, &sMasterConfig) != HAL_OK)
  {
    Error_Handler();
  }
  sConfigOC.OCMode = TIM_OCMODE_PWM1;
  sConfigOC.Pulse = 0;
  sConfigOC.OCPolarity = TIM_OCPOLARITY_HIGH;
  sConfigOC.OCNPolarity = TIM_OCNPOLARITY_HIGH;
  sConfigOC.OCFastMode = TIM_OCFAST_DISABLE;
  sConfigOC.OCIdleState = TIM_OCIDLESTATE_RESET;
  sConfigOC.OCNIdleState = TIM_OCNIDLESTATE_RESET;
  if (HAL_TIM_PWM_ConfigChannel(&htim15, &sConfigOC, TIM_CHANNEL_1) != HAL_OK)
  {
    Error_Handler();
  }
  sBreakDeadTimeConfig.OffStateRunMode = TIM_OSSR_DISABLE;
  sBreakDeadTimeConfig.OffStateIDLEMode = TIM_OSSI_DISABLE;
  sBreakDeadTimeConfig.LockLevel = TIM_LOCKLEVEL_OFF;
  sBreakDeadTimeConfig.DeadTime = 0;
  sBreakDeadTimeConfig.BreakState = TIM_BREAK_DISABLE;
  sBreakDeadTimeConfig.BreakPolarity = TIM_BREAKPOLARITY_HIGH;
  sBreakDeadTimeConfig.BreakFilter = 0;
  sBreakDeadTimeConfig.AutomaticOutput = TIM_AUTOMATICOUTPUT_DISABLE;
  if (HAL_TIMEx_ConfigBreakDeadTime(&htim15, &sBreakDeadTimeConfig) != HAL_OK)
  {
    Error_Handler();
  }
  HAL_TIM_MspPostInit(&htim15);

}

static void MX_USART1_UART_Init(void)
{

  huart1.Instance = USART1;
  huart1.Init.BaudRate = 115200;
  huart1.Init.WordLength = UART_WORDLENGTH_8B;
  huart1.Init.StopBits = UART_STOPBITS_1;
  huart1.Init.Parity = UART_PARITY_NONE;
  huart1.Init.Mode = UART_MODE_TX_RX;
  huart1.Init.HwFlowCtl = UART_HWCONTROL_NONE;
  huart1.Init.OverSampling = UART_OVERSAMPLING_16;
  huart1.Init.OneBitSampling = UART_ONE_BIT_SAMPLE_DISABLE;
  huart1.Init.ClockPrescaler = UART_PRESCALER_DIV1;
  huart1.AdvancedInit.AdvFeatureInit = UART_ADVFEATURE_NO_INIT;
  if (HAL_UART_Init(&huart1) != HAL_OK)
  {
    Error_Handler();
  }
  if (HAL_UARTEx_SetTxFifoThreshold(&huart1, UART_TXFIFO_THRESHOLD_1_8) != HAL_OK)
  {
    Error_Handler();
  }
  if (HAL_UARTEx_SetRxFifoThreshold(&huart1, UART_RXFIFO_THRESHOLD_1_8) != HAL_OK)
  {
    Error_Handler();
  }
  if (HAL_UARTEx_DisableFifoMode(&huart1) != HAL_OK)
  {
    Error_Handler();
  }

}

static void MX_USB_OTG_HS_PCD_Init(void)
{

  hpcd_USB_OTG_HS.Instance = USB_OTG_HS;
  hpcd_USB_OTG_HS.Init.dev_endpoints = 9;
  hpcd_USB_OTG_HS.Init.speed = PCD_SPEED_HIGH;
  hpcd_USB_OTG_HS.Init.phy_itface = USB_OTG_HS_EMBEDDED_PHY;
  hpcd_USB_OTG_HS.Init.Sof_enable = DISABLE;
  hpcd_USB_OTG_HS.Init.low_power_enable = DISABLE;
  hpcd_USB_OTG_HS.Init.lpm_enable = DISABLE;
  hpcd_USB_OTG_HS.Init.use_dedicated_ep1 = DISABLE;
  hpcd_USB_OTG_HS.Init.vbus_sensing_enable = DISABLE;
  hpcd_USB_OTG_HS.Init.dma_enable = DISABLE;
  if (HAL_PCD_Init(&hpcd_USB_OTG_HS) != HAL_OK)
  {
    Error_Handler();
  }

}

/* FMC initialization function */
static void MX_FMC_Init(void)
{

  FMC_NORSRAM_TimingTypeDef Timing = {0};

  /** Perform the SRAM1 memory initialization sequence
  */
  hsram1.Instance = FMC_NORSRAM_DEVICE;
  hsram1.Extended = FMC_NORSRAM_EXTENDED_DEVICE;
  /* hsram1.Init */
  hsram1.Init.NSBank = FMC_NORSRAM_BANK1;
  hsram1.Init.DataAddressMux = FMC_DATA_ADDRESS_MUX_DISABLE;
  hsram1.Init.MemoryType = FMC_MEMORY_TYPE_SRAM;
  hsram1.Init.MemoryDataWidth = FMC_NORSRAM_MEM_BUS_WIDTH_16;
  hsram1.Init.BurstAccessMode = FMC_BURST_ACCESS_MODE_DISABLE;
  hsram1.Init.WaitSignalPolarity = FMC_WAIT_SIGNAL_POLARITY_LOW;
  hsram1.Init.WaitSignalActive = FMC_WAIT_TIMING_BEFORE_WS;
  hsram1.Init.WriteOperation = FMC_WRITE_OPERATION_ENABLE;
  hsram1.Init.WaitSignal = FMC_WAIT_SIGNAL_DISABLE;
  hsram1.Init.ExtendedMode = FMC_EXTENDED_MODE_DISABLE;
  hsram1.Init.AsynchronousWait = FMC_ASYNCHRONOUS_WAIT_DISABLE;
  hsram1.Init.WriteBurst = FMC_WRITE_BURST_DISABLE;
  hsram1.Init.ContinuousClock = FMC_CONTINUOUS_CLOCK_SYNC_ONLY;
  hsram1.Init.WriteFifo = FMC_WRITE_FIFO_ENABLE;
  hsram1.Init.NBLSetupTime = 0;
  hsram1.Init.PageSize = FMC_PAGE_SIZE_NONE;
  hsram1.Init.MaxChipSelectPulse = DISABLE;
  /* Timing */
  Timing.AddressSetupTime = 3;
  Timing.AddressHoldTime = 15;
  Timing.DataSetupTime = 2;
  Timing.DataHoldTime = 2;
  Timing.BusTurnAroundDuration = 2;
  Timing.CLKDivision = 16;
  Timing.DataLatency = 17;
  Timing.AccessMode = FMC_ACCESS_MODE_A;
  /* ExtTiming */

  if (HAL_SRAM_Init(&hsram1, &Timing, NULL) != HAL_OK)
  {
    Error_Handler( );
  }

}

static void MX_GPIO_Init(void)
{
  GPIO_InitTypeDef GPIO_InitStruct = {0};

  /* GPIO Ports Clock Enable */
  __HAL_RCC_GPIOE_CLK_ENABLE();
  __HAL_RCC_GPIOC_CLK_ENABLE();
  __HAL_RCC_GPIOF_CLK_ENABLE();
  __HAL_RCC_GPIOH_CLK_ENABLE();
  __HAL_RCC_GPIOA_CLK_ENABLE();
  __HAL_RCC_GPIOB_CLK_ENABLE();
  __HAL_RCC_GPIOD_CLK_ENABLE();
  __HAL_RCC_GPIOG_CLK_ENABLE();

  /*Configure GPIO pin Output Level */
  HAL_GPIO_WritePin(GPIOE, Spindle_PH_Pin|xAxis_DIR_Pin|xAxis_CS_Pin|Spindle_SLP_Pin
                          |Spindle_MD_Pin, GPIO_PIN_RESET);

  /*Configure GPIO pin Output Level */
  HAL_GPIO_WritePin(GPIOF, LCD_RS_Pin|zAxis_DIR_Pin|zAxis_CS_Pin, GPIO_PIN_RESET);

  /*Configure GPIO pin Output Level */
  HAL_GPIO_WritePin(TouchPanel_CS_GPIO_Port, TouchPanel_CS_Pin, GPIO_PIN_RESET);

  /*Configure GPIO pin Output Level */
  HAL_GPIO_WritePin(GPIOD, yAxis_CS_Pin|yAxis_DIR_Pin, GPIO_PIN_RESET);

  /*Configure GPIO pin Output Level */
  HAL_GPIO_WritePin(Heater_EN_GPIO_Port, Heater_EN_Pin, GPIO_PIN_RESET);

  /*Configure GPIO pin Output Level */
  HAL_GPIO_WritePin(UCPD_DBn_GPIO_Port, UCPD_DBn_Pin, GPIO_PIN_RESET);

  /*Configure GPIO pins : Spindle_PH_Pin xAxis_DIR_Pin xAxis_CS_Pin Spindle_SLP_Pin
                           Spindle_MD_Pin */
  GPIO_InitStruct.Pin = Spindle_PH_Pin|xAxis_DIR_Pin|xAxis_CS_Pin|Spindle_SLP_Pin
                          |Spindle_MD_Pin;
  GPIO_InitStruct.Mode = GPIO_MODE_OUTPUT_PP;
  GPIO_InitStruct.Pull = GPIO_NOPULL;
  GPIO_InitStruct.Speed = GPIO_SPEED_FREQ_LOW;
  HAL_GPIO_Init(GPIOE, &GPIO_InitStruct);

  /*Configure GPIO pin : Spindle_FLT_Pin */
  GPIO_InitStruct.Pin = Spindle_FLT_Pin;
  GPIO_InitStruct.Mode = GPIO_MODE_INPUT;
  GPIO_InitStruct.Pull = GPIO_NOPULL;
  HAL_GPIO_Init(Spindle_FLT_GPIO_Port, &GPIO_InitStruct);

  /*Configure GPIO pins : xAxis_DIAG_Pin zAxis_DIAG_Pin */
  GPIO_InitStruct.Pin = xAxis_DIAG_Pin|zAxis_DIAG_Pin;
  GPIO_InitStruct.Mode = GPIO_MODE_INPUT;
  GPIO_InitStruct.Pull = GPIO_NOPULL;
  HAL_GPIO_Init(GPIOF, &GPIO_InitStruct);

  /*Configure GPIO pins : xAxis_MIN_LIMIT_Pin xAxis_MAX_LIMIT_Pin */
  GPIO_InitStruct.Pin = xAxis_MIN_LIMIT_Pin|xAxis_MAX_LIMIT_Pin;
  GPIO_InitStruct.Mode = GPIO_MODE_IT_FALLING;
  GPIO_InitStruct.Pull = GPIO_PULLUP;
  HAL_GPIO_Init(GPIOF, &GPIO_InitStruct);

  /*Configure GPIO pins : LCD_RS_Pin zAxis_DIR_Pin zAxis_CS_Pin */
  GPIO_InitStruct.Pin = LCD_RS_Pin|zAxis_DIR_Pin|zAxis_CS_Pin;
  GPIO_InitStruct.Mode = GPIO_MODE_OUTPUT_PP;
  GPIO_InitStruct.Pull = GPIO_NOPULL;
  GPIO_InitStruct.Speed = GPIO_SPEED_FREQ_LOW;
  HAL_GPIO_Init(GPIOF, &GPIO_InitStruct);

  /*Configure GPIO pin : tip_LIMIT_Pin */
  GPIO_InitStruct.Pin = tip_LIMIT_Pin;
  GPIO_InitStruct.Mode = GPIO_MODE_INPUT;
  GPIO_InitStruct.Pull = GPIO_PULLUP;
  HAL_GPIO_Init(tip_LIMIT_GPIO_Port, &GPIO_InitStruct);

  /*Configure GPIO pin : zAxis_MIN_LIMIT_Pin */
  GPIO_InitStruct.Pin = zAxis_MIN_LIMIT_Pin;
  GPIO_InitStruct.Mode = GPIO_MODE_IT_FALLING;
  GPIO_InitStruct.Pull = GPIO_PULLUP;
  HAL_GPIO_Init(zAxis_MIN_LIMIT_GPIO_Port, &GPIO_InitStruct);

  /*Configure GPIO pin : zAxis_MAX_LIMIT_Pin */
  GPIO_InitStruct.Pin = zAxis_MAX_LIMIT_Pin;
  GPIO_InitStruct.Mode = GPIO_MODE_IT_RISING_FALLING;
  GPIO_InitStruct.Pull = GPIO_PULLUP;
  HAL_GPIO_Init(zAxis_MAX_LIMIT_GPIO_Port, &GPIO_InitStruct);

  /*Configure GPIO pin : TouchPanel_IRQ_Pin */
  GPIO_InitStruct.Pin = TouchPanel_IRQ_Pin;
  GPIO_InitStruct.Mode = GPIO_MODE_INPUT;
  GPIO_InitStruct.Pull = GPIO_NOPULL;
  HAL_GPIO_Init(TouchPanel_IRQ_GPIO_Port, &GPIO_InitStruct);

  /*Configure GPIO pin : TouchPanel_CS_Pin */
  GPIO_InitStruct.Pin = TouchPanel_CS_Pin;
  GPIO_InitStruct.Mode = GPIO_MODE_OUTPUT_PP;
  GPIO_InitStruct.Pull = GPIO_NOPULL;
  GPIO_InitStruct.Speed = GPIO_SPEED_FREQ_LOW;
  HAL_GPIO_Init(TouchPanel_CS_GPIO_Port, &GPIO_InitStruct);

  /*Configure GPIO pins : yAxis_MAX_LIMIT_Pin yAxis_MIN_LIMIT_Pin */
  GPIO_InitStruct.Pin = yAxis_MAX_LIMIT_Pin|yAxis_MIN_LIMIT_Pin;
  GPIO_InitStruct.Mode = GPIO_MODE_IT_FALLING;
  GPIO_InitStruct.Pull = GPIO_PULLUP;
  HAL_GPIO_Init(GPIOB, &GPIO_InitStruct);

  /*Configure GPIO pins : yAxis_DIAG_Pin UCPD_FLT_Pin */
  GPIO_InitStruct.Pin = yAxis_DIAG_Pin|UCPD_FLT_Pin;
  GPIO_InitStruct.Mode = GPIO_MODE_INPUT;
  GPIO_InitStruct.Pull = GPIO_NOPULL;
  HAL_GPIO_Init(GPIOB, &GPIO_InitStruct);

  /*Configure GPIO pin : PB15 */
  GPIO_InitStruct.Pin = GPIO_PIN_15;
  GPIO_InitStruct.Mode = GPIO_MODE_ANALOG;
  GPIO_InitStruct.Pull = GPIO_NOPULL;
  HAL_GPIO_Init(GPIOB, &GPIO_InitStruct);

  /*Configure GPIO pins : yAxis_CS_Pin yAxis_DIR_Pin */
  GPIO_InitStruct.Pin = yAxis_CS_Pin|yAxis_DIR_Pin;
  GPIO_InitStruct.Mode = GPIO_MODE_OUTPUT_PP;
  GPIO_InitStruct.Pull = GPIO_NOPULL;
  GPIO_InitStruct.Speed = GPIO_SPEED_FREQ_LOW;
  HAL_GPIO_Init(GPIOD, &GPIO_InitStruct);

  /*Configure GPIO pin : Heater_EN_Pin */
  GPIO_InitStruct.Pin = Heater_EN_Pin;
  GPIO_InitStruct.Mode = GPIO_MODE_OUTPUT_PP;
  GPIO_InitStruct.Pull = GPIO_NOPULL;
  GPIO_InitStruct.Speed = GPIO_SPEED_FREQ_LOW;
  HAL_GPIO_Init(Heater_EN_GPIO_Port, &GPIO_InitStruct);

  /*Configure GPIO pin : PA15 */
  GPIO_InitStruct.Pin = GPIO_PIN_15;
  GPIO_InitStruct.Mode = GPIO_MODE_ANALOG;
  GPIO_InitStruct.Pull = GPIO_NOPULL;
  HAL_GPIO_Init(GPIOA, &GPIO_InitStruct);

  /*Configure GPIO pin : UCPD_DBn_Pin */
  GPIO_InitStruct.Pin = UCPD_DBn_Pin;
  GPIO_InitStruct.Mode = GPIO_MODE_OUTPUT_PP;
  GPIO_InitStruct.Pull = GPIO_NOPULL;
  GPIO_InitStruct.Speed = GPIO_SPEED_FREQ_LOW;
  HAL_GPIO_Init(UCPD_DBn_GPIO_Port, &GPIO_InitStruct);

  /* EXTI interrupt init*/
  HAL_NVIC_SetPriority(EXTI0_IRQn, 0, 0);
  HAL_NVIC_EnableIRQ(EXTI0_IRQn);

  HAL_NVIC_SetPriority(EXTI1_IRQn, 0, 0);
  HAL_NVIC_EnableIRQ(EXTI1_IRQn);

  HAL_NVIC_SetPriority(EXTI2_IRQn, 0, 0);
  HAL_NVIC_EnableIRQ(EXTI2_IRQn);

  HAL_NVIC_SetPriority(EXTI3_IRQn, 0, 0);
  HAL_NVIC_EnableIRQ(EXTI3_IRQn);

  HAL_NVIC_SetPriority(EXTI10_IRQn, 0, 0);
  HAL_NVIC_EnableIRQ(EXTI10_IRQn);

  HAL_NVIC_SetPriority(EXTI11_IRQn, 0, 0);
  HAL_NVIC_EnableIRQ(EXTI11_IRQn);

}

/* USER CODE BEGIN 4 */

int _getentropy(void* buffer, size_t length) {
    return -1;
}

/* USER CODE END 4 */

void Error_Handler(void)
{
  /* USER CODE BEGIN Error_Handler_Debug */
    /* User can add his own implementation to report the HAL error return
     * state */
    __disable_irq();
    while (1) {}
  /* USER CODE END Error_Handler_Debug */
}
#ifdef USE_FULL_ASSERT
/**
  * @brief  Reports the name of the source file and the source line number
  *         where the assert_param error has occurred.
  * @param  file: pointer to the source file name
  * @param  line: assert_param error line source number
  * @retval None
  */
void assert_failed(uint8_t *file, uint32_t line)
{
  /* USER CODE BEGIN 6 */
    /* User can add his own implementation to report the file name and
       line number, ex: printf("Wrong parameters value: file %s on line
       %d\r\n", file, line) */
  /* USER CODE END 6 */
}
#endif /* USE_FULL_ASSERT */
